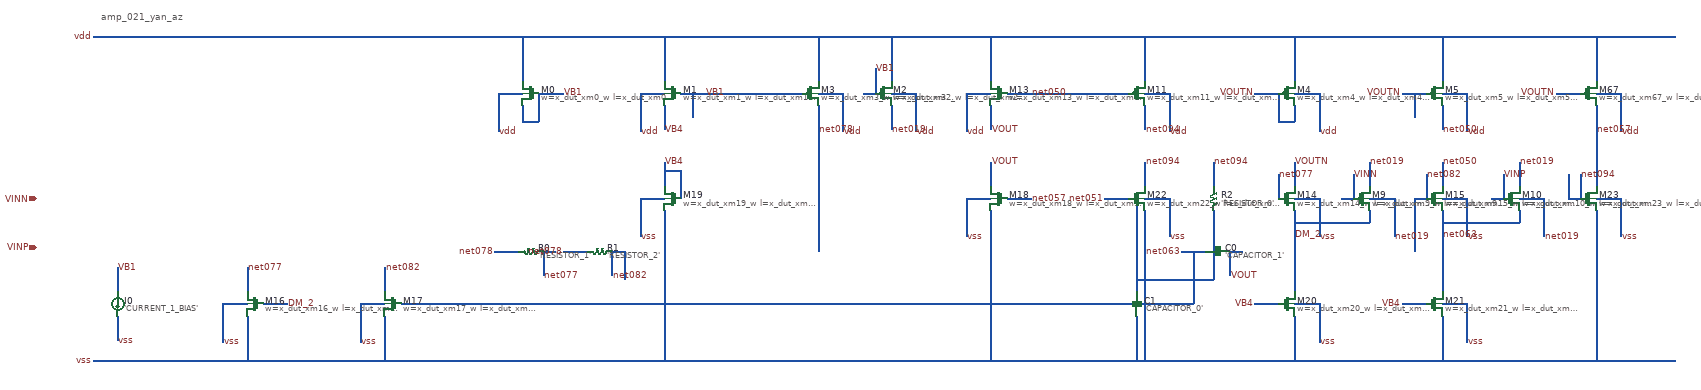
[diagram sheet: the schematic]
v {xschem version=3.4.6 file_version=1.2}
G {}
K {}
V {}
S {}
E {}
T {amp_021_yan_az} -1910 -200 0 0 0.4 0.4 {}
C {devices/capa_np.sym} 845 390 1 0 {name=C0 value='CAPACITOR_1'}
C {devices/capa_np.sym} 645 520 0 0 {name=C1 value='CAPACITOR_0'}
C {devices/isource_np.sym} -1870 520 0 0 {name=I0 value='CURRENT_1_BIAS'}
C {devices/res_np.sym} -850 390 1 0 {name=R0 value='RESISTOR_1'}
C {devices/res_np.sym} -680 390 1 0 {name=R1 value='RESISTOR_2'}
C {devices/res_np.sym} 835 260 0 0 {name=R2 value='RESISTOR_0'}
C {devices/sg13_lv_pmos_np.sym} -850 0 0 1 {name=M0 model=sg13_lv_pmos spiceprefix=X w=x_dut_xm0_w l=x_dut_xm0_l m=x_dut_xm0_m}
C {devices/sg13_lv_pmos_np.sym} -500 0 0 1 {name=M1 model=sg13_lv_pmos spiceprefix=X w=x_dut_xm1_w l=x_dut_xm1_l m=x_dut_xm1_m}
C {devices/sg13_lv_pmos_np.sym} 1570 260 0 0 {name=M10 model=sg13_lv_pmos spiceprefix=X w=x_dut_xm10_w l=x_dut_xm10_l m=x_dut_xm10_m}
C {devices/sg13_lv_pmos_np.sym} 645 0 0 0 {name=M11 model=sg13_lv_pmos spiceprefix=X w=x_dut_xm11_w l=x_dut_xm11_l m=x_dut_xm11_m}
C {devices/sg13_lv_pmos_np.sym} 305 0 0 1 {name=M13 model=sg13_lv_pmos spiceprefix=X w=x_dut_xm13_w l=x_dut_xm13_l m=x_dut_xm13_m}
C {devices/sg13_lv_nmos_np.sym} 1015 260 0 0 {name=M14 model=sg13_lv_nmos spiceprefix=X w=x_dut_xm14_w l=x_dut_xm14_l m=x_dut_xm14_m}
C {devices/sg13_lv_nmos_np.sym} 1380 260 0 0 {name=M15 model=sg13_lv_nmos spiceprefix=X w=x_dut_xm15_w l=x_dut_xm15_l m=x_dut_xm15_m}
C {devices/sg13_lv_nmos_np.sym} -1530 520 0 1 {name=M16 model=sg13_lv_nmos spiceprefix=X w=x_dut_xm16_w l=x_dut_xm16_l m=x_dut_xm16_m}
C {devices/sg13_lv_nmos_np.sym} -1190 520 0 1 {name=M17 model=sg13_lv_nmos spiceprefix=X w=x_dut_xm17_w l=x_dut_xm17_l m=x_dut_xm17_m}
C {devices/sg13_lv_nmos_np.sym} 305 260 0 1 {name=M18 model=sg13_lv_nmos spiceprefix=X w=x_dut_xm18_w l=x_dut_xm18_l m=x_dut_xm18_m}
C {devices/sg13_lv_nmos_np.sym} -500 260 0 1 {name=M19 model=sg13_lv_nmos spiceprefix=X w=x_dut_xm19_w l=x_dut_xm19_l m=x_dut_xm19_m}
C {devices/sg13_lv_pmos_np.sym} 20 0 0 0 {name=M2 model=sg13_lv_pmos spiceprefix=X w=x_dut_xm2_w l=x_dut_xm2_l m=x_dut_xm2_m}
C {devices/sg13_lv_nmos_np.sym} 1015 520 0 0 {name=M20 model=sg13_lv_nmos spiceprefix=X w=x_dut_xm20_w l=x_dut_xm20_l m=x_dut_xm20_m}
C {devices/sg13_lv_nmos_np.sym} 1380 520 0 0 {name=M21 model=sg13_lv_nmos spiceprefix=X w=x_dut_xm21_w l=x_dut_xm21_l m=x_dut_xm21_m}
C {devices/sg13_lv_nmos_np.sym} 645 260 0 0 {name=M22 model=sg13_lv_nmos spiceprefix=X w=x_dut_xm22_w l=x_dut_xm22_l m=x_dut_xm22_m}
C {devices/sg13_lv_nmos_np.sym} 1760 260 0 0 {name=M23 model=sg13_lv_nmos spiceprefix=X w=x_dut_xm23_w l=x_dut_xm23_l m=x_dut_xm23_m}
C {devices/sg13_lv_pmos_np.sym} -160 0 0 0 {name=M3 model=sg13_lv_pmos spiceprefix=X w=x_dut_xm3_w l=x_dut_xm3_l m=x_dut_xm3_m}
C {devices/sg13_lv_pmos_np.sym} 1015 0 0 0 {name=M4 model=sg13_lv_pmos spiceprefix=X w=x_dut_xm4_w l=x_dut_xm4_l m=x_dut_xm4_m}
C {devices/sg13_lv_pmos_np.sym} 1380 0 0 0 {name=M5 model=sg13_lv_pmos spiceprefix=X w=x_dut_xm5_w l=x_dut_xm5_l m=x_dut_xm5_m}
C {devices/sg13_lv_pmos_np.sym} 1760 0 0 0 {name=M67 model=sg13_lv_pmos spiceprefix=X w=x_dut_xm67_w l=x_dut_xm67_l m=x_dut_xm67_m}
C {devices/sg13_lv_pmos_np.sym} 1200 260 0 0 {name=M9 model=sg13_lv_pmos spiceprefix=X w=x_dut_xm9_w l=x_dut_xm9_l m=x_dut_xm9_m}
N -1870 430 -1870 490 {}
N -1870 550 -1870 610 {}
N -1610 520 -1610 614 {}
N -1550 430 -1550 490 {}
N -1550 550 -1550 660 {}
N -1270 520 -1270 614 {}
N -1210 430 -1210 490 {}
N -1210 550 -1210 660 {}
N -930 0 -930 94 {}
N -870 -140 -870 -30 {}
N -870 30 -870 70 {}
N -830 0 -830 70 {}
N -820 390 -820 450 {}
N -650 390 -650 450 {}
N -620 390 -620 460 {}
N -580 0 -580 94 {}
N -580 260 -580 354 {}
N -520 -140 -520 -30 {}
N -520 30 -520 90 {}
N -520 170 -520 230 {}
N -520 290 -520 660 {}
N -480 190 -480 260 {}
N -450 0 -450 60 {}
N -140 -140 -140 -30 {}
N -140 30 -140 390 {}
N -80 0 -80 94 {}
N 0 -60 0 0 {}
N 40 -140 40 -30 {}
N 40 30 40 90 {}
N 100 0 100 94 {}
N 225 0 225 94 {}
N 225 260 225 354 {}
N 285 -140 285 -30 {}
N 285 30 285 90 {}
N 285 170 285 230 {}
N 285 290 285 660 {}
N 645 260 645 490 {}
N 645 550 645 660 {}
N 665 -140 665 -30 {}
N 665 30 665 90 {}
N 665 170 665 230 {}
N 665 290 665 660 {}
N 725 0 725 94 {}
N 725 260 725 354 {}
N 785 390 785 520 {}
N 835 170 835 230 {}
N 835 290 835 460 {}
N 875 390 875 450 {}
N 995 0 995 70 {}
N 995 200 995 260 {}
N 1035 -140 1035 -30 {}
N 1035 30 1035 70 {}
N 1035 170 1035 230 {}
N 1035 290 1035 490 {}
N 1035 550 1035 660 {}
N 1095 0 1095 94 {}
N 1095 260 1095 354 {}
N 1095 520 1095 614 {}
N 1180 200 1180 260 {}
N 1220 170 1220 230 {}
N 1220 290 1220 320 {}
N 1280 260 1280 354 {}
N 1330 0 1330 60 {}
N 1330 260 1330 390 {}
N 1360 200 1360 260 {}
N 1400 -140 1400 -30 {}
N 1400 30 1400 90 {}
N 1400 170 1400 230 {}
N 1400 290 1400 490 {}
N 1400 550 1400 660 {}
N 1460 0 1460 94 {}
N 1460 260 1460 354 {}
N 1460 520 1460 614 {}
N 1550 200 1550 260 {}
N 1590 170 1590 230 {}
N 1590 290 1590 320 {}
N 1650 260 1650 354 {}
N 1710 200 1710 260 {}
N 1740 200 1740 260 {}
N 1780 -140 1780 -30 {}
N 1780 30 1780 230 {}
N 1780 290 1780 660 {}
N 1840 0 1840 94 {}
N 1840 260 1840 354 {}
N -1930 -140 1975 -140 {}
N -930 0 -870 0 {}
N -830 0 -770 0 {}
N -580 0 -520 0 {}
N -480 0 -180 0 {}
N -140 0 -80 0 {}
N -30 0 0 0 {}
N 40 0 100 0 {}
N 225 0 285 0 {}
N 325 0 625 0 {}
N 665 0 725 0 {}
N 935 0 995 0 {}
N 1035 0 1095 0 {}
N 1300 0 1360 0 {}
N 1400 0 1460 0 {}
N 1680 0 1740 0 {}
N 1780 0 1840 0 {}
N -870 70 -830 70 {}
N 995 70 1035 70 {}
N -520 190 -480 190 {}
N -580 260 -520 260 {}
N 225 260 285 260 {}
N 325 260 385 260 {}
N 565 260 645 260 {}
N 665 260 725 260 {}
N 1035 260 1095 260 {}
N 1150 260 1180 260 {}
N 1220 260 1280 260 {}
N 1330 260 1360 260 {}
N 1400 260 1460 260 {}
N 1520 260 1550 260 {}
N 1590 260 1650 260 {}
N 1710 260 1740 260 {}
N 1780 260 1840 260 {}
N 1035 320 1220 320 {}
N 1400 320 1590 320 {}
N -940 390 -880 390 {}
N -820 390 -790 390 {}
N -770 390 -710 390 {}
N -650 390 -620 390 {}
N 755 390 815 390 {}
N 875 390 905 390 {}
N 645 460 835 460 {}
N -1610 520 -1550 520 {}
N -1510 520 -1450 520 {}
N -1270 520 -1210 520 {}
N -1170 520 785 520 {}
N 935 520 995 520 {}
N 1035 520 1095 520 {}
N 1300 520 1360 520 {}
N 1400 520 1460 520 {}
N -1930 660 1975 660 {}
C {devices/lab_wire.sym} -1930 -140 0 0 {name=l0 lab=vdd}
C {devices/lab_wire.sym} -1930 660 0 0 {name=l1 lab=vss}
C {devices/lab_wire.sym} -1450 520 0 1 {name=l2 lab=DM_2}
C {devices/lab_wire.sym} 1035 350 2 0 {name=l3 lab=DM_2}
C {devices/lab_wire.sym} -770 0 0 1 {name=l4 lab=VB1}
C {devices/lab_wire.sym} -420 0 0 1 {name=l5 lab=VB1}
C {devices/lab_wire.sym} 0 -60 0 1 {name=l6 lab=VB1}
C {devices/lab_wire.sym} -520 90 2 0 {name=l7 lab=VB4}
C {devices/lab_wire.sym} -520 170 0 1 {name=l8 lab=VB4}
C {devices/lab_wire.sym} 935 520 0 0 {name=l9 lab=VB4}
C {devices/lab_wire.sym} 1300 520 0 0 {name=l10 lab=VB4}
C {devices/lab_wire.sym} 1180 200 0 1 {name=l11 lab=VINN}
C {devices/lab_wire.sym} 1550 200 0 1 {name=l12 lab=VINP}
C {devices/lab_wire.sym} 285 90 2 0 {name=l13 lab=VOUT}
C {devices/lab_wire.sym} 285 170 0 1 {name=l14 lab=VOUT}
C {devices/lab_wire.sym} 875 450 2 0 {name=l15 lab=VOUT}
C {devices/lab_wire.sym} 935 0 0 0 {name=l16 lab=VOUTN}
C {devices/lab_wire.sym} 1035 170 0 1 {name=l17 lab=VOUTN}
C {devices/lab_wire.sym} 1300 0 0 0 {name=l18 lab=VOUTN}
C {devices/lab_wire.sym} 1680 0 0 0 {name=l19 lab=VOUTN}
C {devices/lab_wire.sym} 40 90 2 0 {name=l20 lab=net019}
C {devices/lab_wire.sym} 1220 170 0 1 {name=l21 lab=net019}
C {devices/lab_wire.sym} 1590 170 0 1 {name=l22 lab=net019}
C {devices/lab_wire.sym} 385 0 0 1 {name=l23 lab=net050}
C {devices/lab_wire.sym} 1400 90 2 0 {name=l24 lab=net050}
C {devices/lab_wire.sym} 1400 170 0 1 {name=l25 lab=net050}
C {devices/lab_wire.sym} 565 260 0 0 {name=l26 lab=net051}
C {devices/lab_wire.sym} 385 260 0 1 {name=l27 lab=net057}
C {devices/lab_wire.sym} 1780 90 2 0 {name=l28 lab=net057}
C {devices/lab_wire.sym} 755 390 0 0 {name=l29 lab=net063}
C {devices/lab_wire.sym} 1400 350 2 0 {name=l30 lab=net063}
C {devices/lab_wire.sym} -1550 430 0 1 {name=l31 lab=net077}
C {devices/lab_wire.sym} -820 450 2 0 {name=l32 lab=net077}
C {devices/lab_wire.sym} 995 200 0 1 {name=l33 lab=net077}
C {devices/lab_wire.sym} -940 390 0 0 {name=l34 lab=net078}
C {devices/lab_wire.sym} -770 390 0 0 {name=l35 lab=net078}
C {devices/lab_wire.sym} -140 90 2 0 {name=l36 lab=net078}
C {devices/lab_wire.sym} -1210 430 0 1 {name=l37 lab=net082}
C {devices/lab_wire.sym} -650 450 2 0 {name=l38 lab=net082}
C {devices/lab_wire.sym} 1360 200 0 1 {name=l39 lab=net082}
C {devices/lab_wire.sym} 665 90 2 0 {name=l40 lab=net094}
C {devices/lab_wire.sym} 665 170 0 1 {name=l41 lab=net094}
C {devices/lab_wire.sym} 835 170 0 1 {name=l42 lab=net094}
C {devices/lab_wire.sym} 1740 200 0 1 {name=l43 lab=net094}
C {devices/lab_wire.sym} 1650 354 2 0 {name=l44 lab=net019}
C {devices/lab_wire.sym} 1280 354 2 0 {name=l45 lab=net019}
C {devices/lab_wire.sym} -930 94 2 0 {name=l46 lab=vdd}
C {devices/lab_wire.sym} -580 94 2 0 {name=l47 lab=vdd}
C {devices/lab_wire.sym} 725 94 2 0 {name=l48 lab=vdd}
C {devices/lab_wire.sym} 225 94 2 0 {name=l49 lab=vdd}
C {devices/lab_wire.sym} 100 94 2 0 {name=l50 lab=vdd}
C {devices/lab_wire.sym} -80 94 2 0 {name=l51 lab=vdd}
C {devices/lab_wire.sym} 1095 94 2 0 {name=l52 lab=vdd}
C {devices/lab_wire.sym} 1460 94 2 0 {name=l53 lab=vdd}
C {devices/lab_wire.sym} 1840 94 2 0 {name=l54 lab=vdd}
C {devices/lab_wire.sym} 1095 354 2 0 {name=l55 lab=vss}
C {devices/lab_wire.sym} 1460 354 2 0 {name=l56 lab=vss}
C {devices/lab_wire.sym} -1610 614 2 0 {name=l57 lab=vss}
C {devices/lab_wire.sym} -1270 614 2 0 {name=l58 lab=vss}
C {devices/lab_wire.sym} 225 354 2 0 {name=l59 lab=vss}
C {devices/lab_wire.sym} -580 354 2 0 {name=l60 lab=vss}
C {devices/lab_wire.sym} 1095 614 2 0 {name=l61 lab=vss}
C {devices/lab_wire.sym} 1460 614 2 0 {name=l62 lab=vss}
C {devices/lab_wire.sym} 725 354 2 0 {name=l63 lab=vss}
C {devices/lab_wire.sym} 1840 354 2 0 {name=l64 lab=vss}
C {devices/lab_wire.sym} -1870 610 2 0 {name=l65 lab=vss}
C {devices/lab_wire.sym} -1870 430 0 1 {name=l66 lab=VB1}
C {devices/ipin.sym} -2070 260 0 0 {name=p0 lab=VINN}
C {devices/ipin.sym} -2070 380 0 0 {name=p1 lab=VINP}
